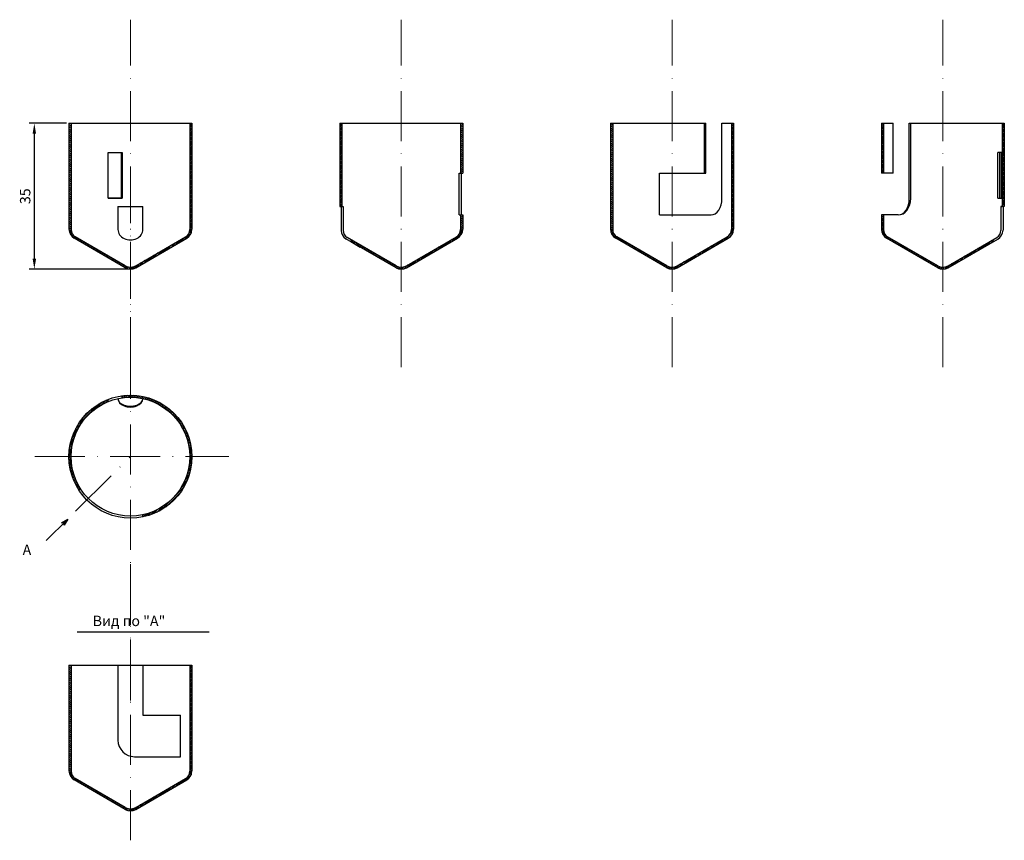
# Model space of a CAD drawing. Units: millimetres. Extents: x 2 to 239, y -121 to 76.
import ezdxf

# ---------------------------------------------------------------- set-up
doc = ezdxf.new("R2010")
doc.units = ezdxf.units.MM
doc.linetypes.add('ACAD_ISO10W100', pattern=[18, 12, -3, 0, -3])
doc.dimstyles.new('ISO-25', dxfattribs={"dimtxt": 2.5, "dimasz": 2.5, "dimexe": 1.25, "dimexo": 0.625, "dimtad": 1, "dimtxsty": 'Standard', "dimcen": 2.5, "dimadec": 0, "dimazin": 0, "dimtfac": 1, "dimtmove": 0, "dimatfit": 3, "dimfxl": 0, "dimarcsym": 0})

# ---------------------------------------------------------------- blocks, each defined once
blk = doc.blocks.new('*D2')
at = {"color": 0, "lineweight": -2}
for p, q in [((13.63, 51), (4.68, 51)), ((5.93, 48.5), (5.93, 18.5)), ((28.38, 16), (4.68, 16))]:
    blk.add_line(p, q, dxfattribs=at)
at = {"color": 0, "lineweight": 15}
for points in [[(5.52, 48.5), (6.35, 48.5), (5.93, 51)], [(5.52, 18.5), (6.35, 18.5), (5.93, 16)]]:
    blk.add_solid(points, dxfattribs=at)
at = {"layer": 'Defpoints', "color": 0, "lineweight": 15}
for p in [(14.25, 51), (5.93, 16), (29, 16)]:
    blk.add_point(p, dxfattribs=at)
at = {"color": 0, "lineweight": 15, "insert": (4.06, 33.5), "char_height": 2.5, "attachment_point": 5, "rotation": 90}
blk.add_mtext('35', dxfattribs=at)

msp = doc.modelspace()

# ---------------------------------------------------------------- hatches: boundary and pattern name
at = {"lineweight": 15}
h = msp.add_hatch(dxfattribs=at)
h.set_pattern_fill('ANSI31', scale=0.1, style=0)
h.paths.add_polyline_path([(14.75, 51), (14.25, 51), (14.25, 25.579, 0.2679492), (15.5, 23.414), (27.762, 16.335, 0.1304702), (29, 16), (29, 16.5, -0.1304702), (27.762, 16.835), (15.75, 23.77, -0.2679492), (14.75, 25.502)])
h.paths.add_polyline_path([(43.75, 51), (43.25, 51), (43.25, 25.488, -0.2679492), (42.25, 23.756), (30.262, 16.835, -0.1328352), (29, 16.5), (29, 16, 0.1328352), (30.262, 16.335), (42.5, 23.401, 0.2679492), (43.75, 25.566)])
h = msp.add_hatch(dxfattribs=at)
h.set_pattern_fill('ANSI31', scale=0.1, style=0)
h.paths.add_polyline_path([(79.75, 51), (79.25, 51), (79.25, 31), (79.558, 31), (79.75, 31)])
h.paths.add_polyline_path([(108.75, 51), (108.25, 51), (108.25, 39), (108.442, 39), (108.75, 39)])
h.paths.add_polyline_path([(108.75, 29), (108.442, 29), (108.25, 29), (108.25, 25.488, -0.2679492), (107.25, 23.756), (95.262, 16.835, -0.1328352), (94, 16.5), (94, 16, 0.1328352), (95.262, 16.335), (107.5, 23.401, 0.2679492), (108.75, 25.566)])
h.paths.add_polyline_path([(82.083, 23), (81.867, 22.625), (84.176, 21.292), (92.762, 16.335, 0.1304702), (94, 16), (94, 16.5, -0.1304702), (92.762, 16.835)])
h = msp.add_hatch(dxfattribs=at)
h.set_pattern_fill('ANSI31', scale=0.1, style=0)
h.paths.add_polyline_path([(144.75, 51), (144.25, 51), (144.25, 25.579, 0.2679492), (145.5, 23.414), (157.762, 16.335, 0.2679492), (160.262, 16.335), (172.5, 23.401, 0.2679492), (173.75, 25.566), (173.75, 51), (173.25, 51), (173.25, 25.488, -0.2679492), (172.25, 23.756), (160.262, 16.835, -0.2679492), (157.762, 16.835), (145.75, 23.77, -0.2679492), (144.75, 25.502)])
h = msp.add_hatch(dxfattribs=at)
h.set_pattern_fill('ANSI31', scale=0.1, style=0)
h.paths.add_polyline_path([(209.75, 51), (209.25, 51), (209.25, 39), (209.75, 39)])
h.paths.add_polyline_path([(238.75, 51), (238.25, 51), (238.25, 31), (238.442, 31), (238.75, 31)])
h = msp.add_hatch(dxfattribs=at)
h.set_pattern_fill('ANSI31', scale=0.1, style=0)
h.paths.add_polyline_path([(209.75, 29), (209.25, 29), (209.25, 25.579, 0.2679492), (210.5, 23.414), (222.762, 16.335, 0.1304702), (224, 16), (224, 16.5, -0.1304702), (222.762, 16.835), (210.75, 23.77, -0.2679492), (209.75, 25.502)])
h.paths.add_polyline_path([(236.133, 22.612), (235.917, 22.987), (225.262, 16.835, -0.1328352), (224, 16.5), (224, 16, 0.1328352), (225.262, 16.335)])
h = msp.add_hatch(dxfattribs=at)
h.set_pattern_fill('ANSI31', scale=0.1, style=0)
h.paths.add_polyline_path([(23.622, -15.804), (23.493, -15.316, 0.3061066), (14.25, -29), (14.75, -29, -0.3049082)])
h.paths.add_polyline_path([(14.75, -29), (14.25, -29, 0.1455896), (16.648, -37.062), (17.017, -36.711, -0.1439233)])
h.paths.add_polyline_path([(29, -14.25, 0.0363084), (26.866, -14.405), (26.998, -14.891, -0.0352604), (29, -14.75)])
h.paths.add_polyline_path([(29, -14.25), (29, -14.75, -0.4142136), (43.25, -29), (43.75, -29, 0.4142136)])
h.paths.add_polyline_path([(43.75, -29), (43.25, -29, -0.3533665), (32, -42.931), (32, -43.442, 0.3554191)])
at = {"lineweight": 30}
h = msp.add_hatch(color=3, dxfattribs=at)
h.paths.add_polyline_path([(13.957, -43.961), (12.448, -44.852, -0.2679492), (12.931, -44.982)])
h.paths.add_polyline_path([(13.957, -43.961), (12.931, -44.982, -0.2679492), (13.059, -45.466)])
at = {"lineweight": 15}
h = msp.add_hatch(dxfattribs=at)
h.set_pattern_fill('ANSI31', scale=0.1, style=0)
h.set_pattern_definition([(45, (0, -130), (-0.2245064, 0.2245064), [])])
h.paths.add_polyline_path([(14.75, -79), (14.25, -79), (14.25, -104.421, 0.2679492), (15.5, -106.586), (27.762, -113.665, 0.1304702), (29, -114), (29, -113.5, -0.1304702), (27.762, -113.165), (15.75, -106.23, -0.2679492), (14.75, -104.498)])
h.paths.add_polyline_path([(43.75, -79), (43.25, -79), (43.25, -104.512, -0.2679492), (42.25, -106.244), (30.262, -113.165, -0.1328352), (29, -113.5), (29, -114, 0.1328352), (30.262, -113.665), (42.5, -106.599, 0.2679492), (43.75, -104.434)])

# ---------------------------------------------------------------- linework, layer by layer
at = {"color": 1, "linetype": 'ACAD_ISO10W100', "lineweight": 15}
for p, q in [((29, -7.554), (29, 75.87)), ((94, -7.554), (94, 75.87)), ((159, -7.554), (159, 75.87)), ((224, -7.554), (224, 75.87)), ((29, 39), (29, -9)), ((29, -87.554), (29, -4.13)), ((6.024, -29), (52.641, -29)), ((15.847, -42.082), (29, -29)), ((29, -121.072), (29, -54.13))]:
    msp.add_line(p, q, dxfattribs=at)
at = {"color": 7, "lineweight": 30}
for p, q in [((14.25, 51), (43.75, 51)), ((14.25, 51), (14.25, 25.579)), ((14.75, 51), (14.75, 25.502)), ((43.25, 51), (43.25, 25.488)), ((43.75, 51), (43.75, 25.566)), ((79.25, 51), (79.25, 31)), ((79.25, 51), (108.75, 51)), ((79.75, 51), (79.75, 31)), ((108.25, 51), (108.25, 39)), ((108.75, 51), (108.75, 39)), ((144.25, 51), (167.129, 51)), ((144.25, 51), (144.25, 25.579)), ((144.75, 51), (144.75, 25.502)), ((166.776, 39), (166.776, 51)), ((167.129, 39), (167.129, 51)), ((170.983, 51), (173.75, 51)), ((170.983, 33), (170.983, 51)), ((173.25, 51), (173.25, 25.488)), ((173.75, 51), (173.75, 25.566)), ((209.25, 51), (212.059, 51)), ((209.25, 51), (209.25, 39)), ((209.75, 51), (209.75, 39)), ((212.059, 39), (212.059, 51)), ((215.938, 33), (215.938, 51)), ((215.938, 51), (238.75, 51)), ((216.289, 33), (216.289, 51)), ((238.25, 51), (238.25, 31)), ((238.75, 51), (238.75, 31)), ((23.652, 44), (27, 44)), ((23.652, 33), (23.652, 44)), ((23.652, 44), (27, 44)), ((26.866, 33), (26.866, 44)), ((27, 44), (27, 33)), ((237.196, 33), (237.196, 44)), ((238.109, 44), (237.196, 44)), ((237.684, 33), (237.684, 44)), ((238.109, 33), (238.109, 44)), ((107.931, 39), (108.442, 39)), ((107.931, 29), (107.931, 39)), ((108.442, 39), (108.75, 39)), ((108.442, 29), (108.442, 39)), ((156, 29), (156, 39)), ((156, 39), (167.129, 39)), ((212.059, 39), (209.25, 39)), ((23.652, 33), (27, 33)), ((27, 33), (23.652, 33)), ((26, 31), (32, 31)), ((26, 31), (26, 25.502)), ((32, 25.502), (32, 31)), ((79.25, 31), (79.558, 31)), ((79.558, 31), (79.558, 25.286)), ((79.558, 31), (80.058, 31)), ((80.058, 31), (80.058, 25.324)), ((237.196, 33), (238.109, 33)), ((237.931, 31), (238.25, 31)), ((238.442, 31), (237.942, 31)), ((237.942, 31), (237.942, 25.31)), ((238.75, 31), (238.442, 31)), ((238.442, 31), (238.442, 25.388)), ((107.931, 29), (108.442, 29)), ((108.25, 29), (108.25, 25.488)), ((108.442, 29), (108.75, 29)), ((108.75, 29), (108.75, 25.566)), ((156, 29), (168.368, 29)), ((209.25, 29), (209.25, 25.579)), ((213.262, 29), (209.25, 29)), ((209.75, 29), (209.75, 25.502)), ((27.762, 16.835), (15.75, 23.77)), ((30.262, 16.835), (42.25, 23.756)), ((95.262, 16.835), (107.25, 23.756)), ((157.762, 16.835), (145.75, 23.77)), ((160.262, 16.835), (172.25, 23.756)), ((222.762, 16.835), (210.75, 23.77)), ((27.762, 16.335), (15.5, 23.414)), ((30.262, 16.335), (42.5, 23.401)), ((92.762, 16.335), (80.708, 23.294)), ((80.708, 23.294), (81.867, 22.625)), ((92.762, 16.835), (81.058, 23.592)), ((81.867, 22.625), (82.083, 23)), ((81.867, 22.625), (84.176, 21.292)), ((95.262, 16.335), (107.5, 23.401)), ((157.762, 16.335), (145.5, 23.414)), ((160.262, 16.335), (172.5, 23.401)), ((222.762, 16.335), (210.5, 23.414)), ((225.262, 16.835), (236.942, 23.578)), ((225.262, 16.335), (237.192, 23.223)), ((235.917, 22.987), (236.133, 22.612)), ((23.493, -15.316), (23.622, -15.804)), ((26.866, -14.405), (26.998, -14.891)), ((16.648, -37.062), (17.017, -36.711)), ((32, -43.442), (32, -42.931)), ((14.25, -79), (14.25, -104.421)), ((14.25, -79), (43.75, -79)), ((14.75, -79), (14.75, -104.498)), ((26, -79), (26, -97)), ((32, -79), (32, -91)), ((43.25, -79), (43.25, -104.512)), ((43.75, -79), (43.75, -104.434)), ((32, -91), (41, -91)), ((41, -101), (41, -91)), ((30, -101), (41, -101)), ((27.762, -113.165), (15.75, -106.23)), ((30.262, -113.165), (42.25, -106.244)), ((27.762, -113.665), (15.5, -106.586)), ((30.262, -113.665), (42.5, -106.599))]:
    msp.add_line(p, q, dxfattribs=at)
at = {"color": 3, "lineweight": 30}
for p, q in [((13.957, -43.961), (8.808, -49.083)), ((12.448, -44.852), (13.957, -43.961)), ((13.957, -43.961), (12.931, -44.982)), ((13.957, -43.961), (13.059, -45.466)), ((16.235, -71.056), (47.888, -71.056))]:
    msp.add_line(p, q, dxfattribs=at)
at = {"color": 7, "lineweight": 30}
for radius in [14.75, 14.25]:
    msp.add_circle((29, -29), radius, dxfattribs=at)
for centre, radius, start, end in [((16.75, 25.579), 2.5, 180, 240), ((16.75, 25.502), 2, 180, 240), ((41.25, 25.488), 2, 300, 0), ((41.25, 25.566), 2.5, 300, 0), ((81.858, 25.286), 2.3, 180, 240), ((82.058, 25.324), 2, 180, 240), ((106.25, 25.488), 2, 300, 0), ((106.25, 25.566), 2.5, 300, 0), ((146.75, 25.579), 2.5, 180, 240), ((146.75, 25.502), 2, 180, 240), ((171.25, 25.488), 2, 300, 0), ((171.25, 25.566), 2.5, 300, 0), ((211.75, 25.579), 2.5, 180, 240), ((211.75, 25.502), 2, 180, 240), ((235.942, 25.31), 2, 300, 0), ((235.942, 25.388), 2.5, 300, 0), ((29.012, 19), 2.5, 240, 300), ((94.012, 19), 2.5, 240, 300), ((159.012, 19), 2.5, 240, 300), ((224.012, 19), 2.5, 240, 300), ((29.012, 18.5), 2.5, 240, 300), ((94.012, 18.5), 2.5, 240, 300), ((159.012, 18.5), 2.5, 240, 300), ((224.012, 18.5), 2.5, 240, 300), ((30, -97), 4, 180, 270), ((16.75, -104.421), 2.5, 180, 240), ((16.75, -104.498), 2, 180, 240), ((41.25, -104.512), 2, 300, 0), ((41.25, -104.434), 2.5, 300, 0), ((29.012, -111), 2.5, 240, 300), ((29.012, -111.5), 2.5, 240, 300)]:
    msp.add_arc(centre, radius, start, end, dxfattribs=at)
at = {"color": 3, "lineweight": 30}
msp.add_arc((12.576, -45.335), 0.5, 344.84448, 106.31884, dxfattribs=at)
at = {"color": 7, "lineweight": 30}
for centre, major_axis, ratio, end_param in [((168.368, 33), (0, -4), 0.6537901, 1.5707963), ((213.262, 33), (0, -4), 0.756676, 1.5707963), ((213.262, 33), (0, -4), 0.6688343, 1.5707963), ((29, 25.502), (-3, 0), 0.8339582, 3.1415927), ((29, -15.069), (-3, 0), 0.6713351, 3.1415927), ((29, -15.069), (-3, 0), 0.5991664, 3.1415927)]:
    msp.add_ellipse(centre, major_axis=major_axis, ratio=ratio, start_param=0, end_param=end_param, dxfattribs=at)

# ---------------------------------------------------------------- texts
at = {"color": 3, "lineweight": 30}
for s, p in [('  А', (1.595, -52.601)), (' Вид по "А"', (19.172, -69.671))]:
    msp.add_text(s, height=2.5, dxfattribs=at).set_placement(p)

# ---------------------------------------------------------------- dimensions: what is measured, and where the dimension line sits
at = {"color": 3, "lineweight": 15}
dim = msp.add_linear_dim(base=(5.933, 16), p1=(14.25, 51), p2=(29, 16), angle=90, dimstyle='ISO-25', dxfattribs=at)
dim.commit()
dim.dimension.update_dxf_attribs({"geometry": '*D2', "text_midpoint": (4.058, 33.5)})

doc.saveas('drawing.dxf')
